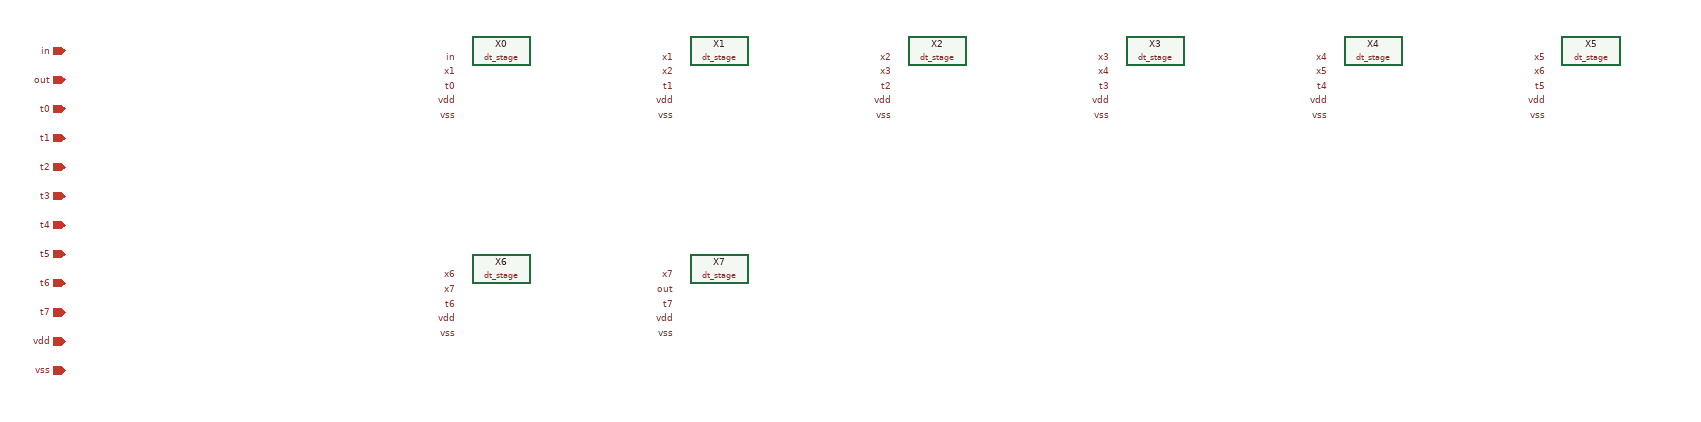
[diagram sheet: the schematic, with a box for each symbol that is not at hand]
v {xschem version=3.4.7RC file_version=1.2}
G {}
K {}
V {}
S {}
E {}

C {devices/iopin.sym} -600 0 0 0 {name=p0 lab=in}
C {devices/iopin.sym} -600 40 0 0 {name=p1 lab=out}
C {devices/iopin.sym} -600 80 0 0 {name=p2 lab=t0}
C {devices/iopin.sym} -600 120 0 0 {name=p3 lab=t1}
C {devices/iopin.sym} -600 160 0 0 {name=p4 lab=t2}
C {devices/iopin.sym} -600 200 0 0 {name=p5 lab=t3}
C {devices/iopin.sym} -600 240 0 0 {name=p6 lab=t4}
C {devices/iopin.sym} -600 280 0 0 {name=p7 lab=t5}
C {devices/iopin.sym} -600 320 0 0 {name=p8 lab=t6}
C {devices/iopin.sym} -600 360 0 0 {name=p9 lab=t7}
C {devices/iopin.sym} -600 400 0 0 {name=p10 lab=vdd}
C {devices/iopin.sym} -600 440 0 0 {name=p11 lab=vss}
C {dt_stage.sym} 0 0 0 0 {name=X0 }
C {devices/lab_pin.sym} -60.0 10.0 0 0 {name=l0 lab=in}
C {devices/lab_pin.sym} -60.0 30.0 0 0 {name=l1 lab=x1}
C {devices/lab_pin.sym} -60.0 50.0 0 0 {name=l2 lab=t0}
C {devices/lab_pin.sym} -60.0 70.0 0 0 {name=l3 lab=vdd}
C {devices/lab_pin.sym} -60.0 90.0 0 0 {name=l4 lab=vss}
C {dt_stage.sym} 300 0 0 0 {name=X1 }
C {devices/lab_pin.sym} 240.0 10.0 0 0 {name=l5 lab=x1}
C {devices/lab_pin.sym} 240.0 30.0 0 0 {name=l6 lab=x2}
C {devices/lab_pin.sym} 240.0 50.0 0 0 {name=l7 lab=t1}
C {devices/lab_pin.sym} 240.0 70.0 0 0 {name=l8 lab=vdd}
C {devices/lab_pin.sym} 240.0 90.0 0 0 {name=l9 lab=vss}
C {dt_stage.sym} 600 0 0 0 {name=X2 }
C {devices/lab_pin.sym} 540.0 10.0 0 0 {name=l10 lab=x2}
C {devices/lab_pin.sym} 540.0 30.0 0 0 {name=l11 lab=x3}
C {devices/lab_pin.sym} 540.0 50.0 0 0 {name=l12 lab=t2}
C {devices/lab_pin.sym} 540.0 70.0 0 0 {name=l13 lab=vdd}
C {devices/lab_pin.sym} 540.0 90.0 0 0 {name=l14 lab=vss}
C {dt_stage.sym} 900 0 0 0 {name=X3 }
C {devices/lab_pin.sym} 840.0 10.0 0 0 {name=l15 lab=x3}
C {devices/lab_pin.sym} 840.0 30.0 0 0 {name=l16 lab=x4}
C {devices/lab_pin.sym} 840.0 50.0 0 0 {name=l17 lab=t3}
C {devices/lab_pin.sym} 840.0 70.0 0 0 {name=l18 lab=vdd}
C {devices/lab_pin.sym} 840.0 90.0 0 0 {name=l19 lab=vss}
C {dt_stage.sym} 1200 0 0 0 {name=X4 }
C {devices/lab_pin.sym} 1140.0 10.0 0 0 {name=l20 lab=x4}
C {devices/lab_pin.sym} 1140.0 30.0 0 0 {name=l21 lab=x5}
C {devices/lab_pin.sym} 1140.0 50.0 0 0 {name=l22 lab=t4}
C {devices/lab_pin.sym} 1140.0 70.0 0 0 {name=l23 lab=vdd}
C {devices/lab_pin.sym} 1140.0 90.0 0 0 {name=l24 lab=vss}
C {dt_stage.sym} 1500 0 0 0 {name=X5 }
C {devices/lab_pin.sym} 1440.0 10.0 0 0 {name=l25 lab=x5}
C {devices/lab_pin.sym} 1440.0 30.0 0 0 {name=l26 lab=x6}
C {devices/lab_pin.sym} 1440.0 50.0 0 0 {name=l27 lab=t5}
C {devices/lab_pin.sym} 1440.0 70.0 0 0 {name=l28 lab=vdd}
C {devices/lab_pin.sym} 1440.0 90.0 0 0 {name=l29 lab=vss}
C {dt_stage.sym} 0 300 0 0 {name=X6 }
C {devices/lab_pin.sym} -60.0 310.0 0 0 {name=l30 lab=x6}
C {devices/lab_pin.sym} -60.0 330.0 0 0 {name=l31 lab=x7}
C {devices/lab_pin.sym} -60.0 350.0 0 0 {name=l32 lab=t6}
C {devices/lab_pin.sym} -60.0 370.0 0 0 {name=l33 lab=vdd}
C {devices/lab_pin.sym} -60.0 390.0 0 0 {name=l34 lab=vss}
C {dt_stage.sym} 300 300 0 0 {name=X7 }
C {devices/lab_pin.sym} 240.0 310.0 0 0 {name=l35 lab=x7}
C {devices/lab_pin.sym} 240.0 330.0 0 0 {name=l36 lab=out}
C {devices/lab_pin.sym} 240.0 350.0 0 0 {name=l37 lab=t7}
C {devices/lab_pin.sym} 240.0 370.0 0 0 {name=l38 lab=vdd}
C {devices/lab_pin.sym} 240.0 390.0 0 0 {name=l39 lab=vss}
